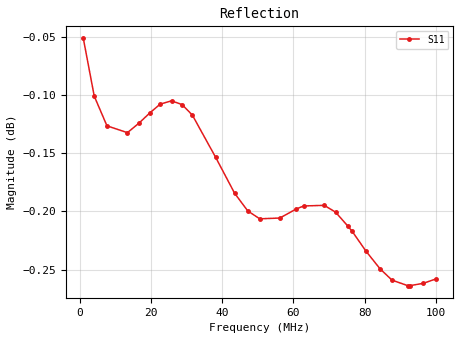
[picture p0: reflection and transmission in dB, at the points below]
# MHz S RI R 50.0
! SimSmith 18.4g
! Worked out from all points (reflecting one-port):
!   1000 points, 1 MHz to 100 MHz, reference 50 ohm
!   lowest |S11| = -0.3 dB at 92.77 MHz (marker M1), VSWR 65.76, Z = 2.76 + j81 ohm
!   phase of S11 starts at 171 deg and turns -892 deg over the sweep
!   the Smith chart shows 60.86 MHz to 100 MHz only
!   S11 on the Smith chart (normalised r, x): 60.86 MHz: 2, -12; 68.68 MHz: 0.03, -1.20; 76.51 MHz: 0.01, -0.27; 84.34 MHz: 0.02, +0.37; 92.17 MHz: 0.05, +1.46; 100 MHz: 34, -34
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1  -0.9809 0.1614
4.072072  -0.7861 0.5992
7.63964  -0.3436 0.9237
13.38739  0.5127 0.8409
16.65766  0.8601 0.4817
19.63063  0.9858 0.0439
22.6036  0.9012 -0.4041
25.77478  0.5991 -0.7856
28.74775  0.1809 -0.9709
31.62162  -0.2615 -0.9513
38.16216  -0.9466 -0.2631
43.51351  -0.8226 0.5308
47.18018  -0.3984 0.8924
50.54955  0.1074 0.9706
56.1982  0.8204 0.5298
60.85586  0.9654 -0.1532
62.93694  0.8655 -0.4549
68.68469  0.179 -0.9613
71.85586  -0.3024 -0.9292
75.32432  -0.74 -0.6361
76.51351  -0.8451 -0.4869
80.37838  -0.9698 0.0839
84.34234  -0.7364 0.634
87.71171  -0.3141 0.9184
92.17117  0.3522 0.9039
92.76577  0.435 0.8671
96.53153  0.8447 0.4775
100  0.9703 -0.029
